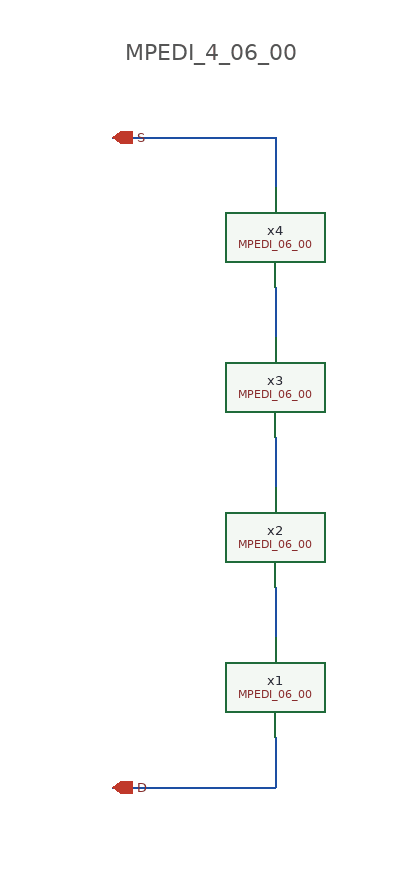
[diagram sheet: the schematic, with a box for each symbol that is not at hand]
v {xschem version=3.4.4 file_version=1.2
}
G {}
K {}
V {}
S {}
E {}
T {MPEDI_4_06_00} -120 -340 0 0 1 1 {}
N -130 -260 -0 -260 {
lab=S}
N -0 -260 0 -220 {
lab=S}
N 0 -140 -0 -100 {
lab=#net1}
N -0 -20 0 20 {
lab=#net2}
N -0 100 -0 140 {
lab=#net3}
N -130 260 0 260 {
lab=D}
N 0 220 -0 260 {
lab=D}
C {iopin.sym} -130 -260 0 1 {name=p1 lab=S}
C {iopin.sym} -130 260 0 1 {name=p2 lab=D}
C {IP62_2_ESD/MPEDI_06_00.sym} -40 -170 0 0 {name=x4}
C {IP62_2_ESD/MPEDI_06_00.sym} -40 -50 0 0 {name=x3}
C {IP62_2_ESD/MPEDI_06_00.sym} -40 70 0 0 {name=x2}
C {IP62_2_ESD/MPEDI_06_00.sym} -40 190 0 0 {name=x1}
